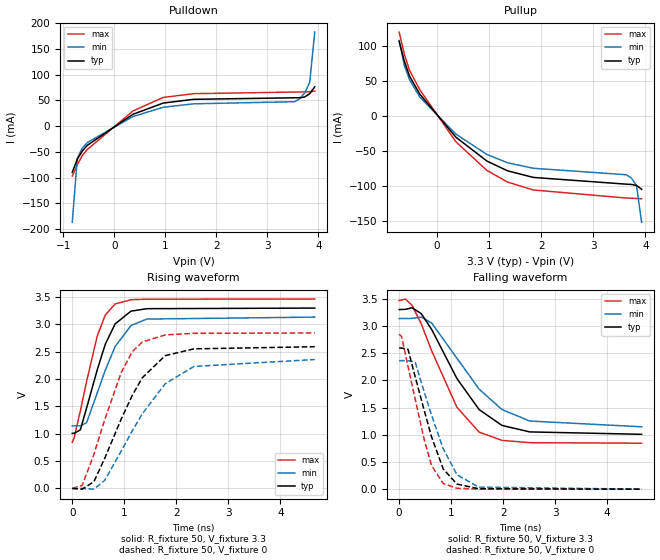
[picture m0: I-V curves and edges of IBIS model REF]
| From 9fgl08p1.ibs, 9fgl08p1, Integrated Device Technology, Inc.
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[Model]   REF
Model_type   Output
Polarity   Non-Inverting
|   typ   min   max
C_comp   2pF   1.5pF   2.5pF
Vmeas = 1.65V
Rref = 50
Cref = 0
Vref = 1.65V
|   typ   min   max
[Voltage range]   3.3V   3.135V   3.465V
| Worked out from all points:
|   slope of the pulldown table from 0 to 0.495 V, typ, clamps not added: 16.9 ohm
|   slope of the pullup table from 0 to 0.495 V, typ, clamps not added: 12.6 ohm
|   rising waveform, R_fixture 50, V_fixture 3.3: 20-80 % time 450ps typ, 507ps min, 388ps max; typ from 1.01 V to 3.3 V
|   falling waveform, R_fixture 50, V_fixture 3.3: 20-80 % time 857ps typ, 970ps min, 739ps max; typ from 3.3 V to 1.01 V
|   rising waveform, R_fixture 50, V_fixture 0: 20-80 % time 771ps typ, 936ps min, 618ps max; typ from 0 V to 2.59 V
|   falling waveform, R_fixture 50, V_fixture 0: 20-80 % time 472ps typ, 527ps min, 413ps max; typ from 2.59 V to 0 V
[Pulldown]
|Voltage   I (typ)   I (min)   I (max)
|Note, modeling breaks down at 250mA and above.  This is well beyond the functional   |
|operating range of the device.  Should this scenario occur, catastrophic failure and   |
|possible damage to the device and/or board is of higher concern than the I-V curve   |
|behavior.  The IBIS checker will flag currents in excess of 10A with warnings.  Lines   |
|with currents in excess of 0.35 A have been commented out.  The points still remain|
|available to the user if the user desires to use them.   |
|-3.30000e+00   -4.58626e+02   -3.98855e+02   -5.58913e+02
|-3.20100e+00   -4.38670e+02   -3.81813e+02   -5.34126e+02
|-3.10200e+00   -4.18718e+02   -3.64776e+02   -5.09343e+02
|-3.00300e+00   -3.98770e+02   -3.47745e+02   -4.84563e+02
|-2.90400e+00   -3.78827e+02   -3.30720e+02   -4.59787e+02
|-2.80500e+00   -3.58890e+02   -3.13701e+02   -4.35015e+02
|-2.70600e+00   -3.38959e+02   -2.96690e+02   -4.10248e+02
|-2.60700e+00   -3.19035e+02   -2.79688e+02   -3.85486e+02
|-2.50800e+00   -2.99119e+02   -2.62696e+02   -3.60731e+02
|-2.40900e+00   -2.79213e+02   -2.45715e+02   -3.35984e+02
|-2.31000e+00   -2.59319e+02   -2.28747e+02   -3.11245e+02
|-2.21100e+00   -2.39437e+02   -2.11796e+02   -2.86516e+02
|-2.11200e+00   -2.19572e+02   -1.94864e+02   -2.61800e+02
|-2.01300e+00   -1.99726e+02   -1.77955e+02   -2.37100e+02
|-1.91400e+00   -1.79905e+02   -1.61075e+02   -2.12419e+02
|-1.81500e+00   -1.60116e+02   -1.44233e+02   -1.87763e+02
|-1.71600e+00   -1.40369e+02   -1.27441e+02   -1.63140e+02
|-1.61700e+00   -1.20682e+02   -1.10717e+02   -1.38565e+02
|-1.51800e+00   -1.01080e+02   -9.40899e+01   -1.14061e+02
|-1.41900e+00   -8.16135e+01   -7.76121e+01   -8.96701e+01
|-1.32000e+00   -6.23864e+01   -6.13830e+01   -6.54941e+01
|-1.22100e+00   -4.36066e+01   -4.55730e+01   -4.17841e+01
|-1.12200e+00   -2.55446e+01   -3.03740e+01   -1.89497e+01
|-1.02300e+00   -8.13369e+00   -1.57511e+01   -1.01906e+00
|-9.24000e-01   -3.55892e-01   -2.38948e+00   -1.27879e-01
-825mV    -89.74mA   -186.9mA   -97.05mA
-726mV    -64.34mA   -62.46mA   -75.03mA
-627mV    -48.3mA    -42.65mA   -56.86mA
-528mV    -37.22mA   -31.89mA   -45.33mA
363mV     22.88mA    18.45mA    29.33mA
957mV     44.74mA    36.62mA    55.73mA
1.551V    52.05mA    43.3mA     63.04mA
3.531V    55.03mA    47.39mA    66.19mA
3.63V     55.21mA    52.95mA    66.32mA
3.729V    56.59mA    64.36mA    66.46mA
3.828V    63.02mA    84.81mA    66.64mA
3.927V    76.26mA    182.8mA    67.99mA
| 4.02600e+00   9.63336e-02   1.95544e+00   7.56685e-02
| 4.12500e+00   1.29319e-01   1.96109e+01   9.19025e-02
| 4.22400e+00   6.62462e-01   4.21550e+01   1.15435e-01
| 4.32300e+00   1.51637e+01   6.47670e+01   1.37492e-01
| 4.42200e+00   4.22442e+01   8.74545e+01   2.35006e-01
| 4.52100e+00   6.94172e+01   1.10195e+02   8.92943e+00
| 4.62000e+00   9.66780e+01   1.32968e+02   4.35589e+01
| 4.71900e+00   1.23991e+02   1.55761e+02   7.83218e+01
| 4.81800e+00   1.51333e+02   1.78569e+02   1.13180e+02
| 4.91700e+00   1.78693e+02   2.01386e+02   1.48085e+02
| 5.01600e+00   2.06065e+02   2.24210e+02   1.83014e+02
| 5.11500e+00   2.33446e+02   2.47041e+02   2.17958e+02
| 5.21400e+00   2.60834e+02   2.69877e+02   2.52912e+02
| 5.31300e+00   2.88228e+02   2.92717e+02   2.87874e+02
| 5.41200e+00   3.15625e+02   3.15560e+02   3.22841e+02
| 5.51100e+00   3.43027e+02   3.38407e+02   3.57813e+02
| 5.61000e+00   3.70432e+02   3.61256e+02   3.92789e+02
| 5.70900e+00   3.97841e+02   3.84108e+02   4.27769e+02
| 5.80800e+00   4.25252e+02   4.06963e+02   4.62752e+02
| 5.90700e+00   4.52666e+02   4.29821e+02   4.97738e+02
| 6.00600e+00   4.80082e+02   4.52680e+02   5.32727e+02
| 6.10500e+00   5.07501e+02   4.75543e+02   5.67718e+02
| 6.20400e+00   5.34922e+02   4.98407e+02   6.02711e+02
| 6.30300e+00   5.62345e+02   5.21273e+02   6.37705e+02
| 6.40200e+00   5.89770e+02   5.44142e+02   6.72701e+02
| 6.50100e+00   6.17197e+02   5.67013e+02   7.07699e+02
| 6.60000e+00   6.44626e+02   5.89886e+02   7.42698e+02
[Pullup]
|Voltage   I (typ)   I (min)   I (max)
|Note, modeling breaks down at 250mA and above.  This is well beyond the functional   |
|operating range of the device.  Should this scenario occur, catastrophic failure and   |
|possible damage to the device and/or board is of higher concern than the I-V curve   |
|behavior.  The IBIS checker will flag currents in excess of 10A with warnings.  Lines   |
|with currents in excess of 0.35 A have been commented out.  The points still remain|
|available to the user if the user desires to use them.   |
|-3.30000e+00   6.44680e+02   5.51825e+02   8.01095e+02
|-3.20100e+00   6.17254e+02   5.28958e+02   7.66095e+02
|-3.10200e+00   5.89830e+02   5.06093e+02   7.31096e+02
|-3.00300e+00   5.62407e+02   4.83230e+02   6.96098e+02
|-2.90400e+00   5.34987e+02   4.60368e+02   6.61102e+02
|-2.80500e+00   5.07568e+02   4.37509e+02   6.26108e+02
|-2.70600e+00   4.80150e+02   4.14651e+02   5.91115e+02
|-2.60700e+00   4.52735e+02   3.91796e+02   5.56124e+02
|-2.50800e+00   4.25322e+02   3.68942e+02   5.21136e+02
|-2.40900e+00   3.97911e+02   3.46091e+02   4.86149e+02
|-2.31000e+00   3.70503e+02   3.23243e+02   4.51165e+02
|-2.21100e+00   3.43097e+02   3.00397e+02   4.16183e+02
|-2.11200e+00   3.15694e+02   2.77554e+02   3.81204e+02
|-2.01300e+00   2.88295e+02   2.54715e+02   3.46229e+02
|-1.91400e+00   2.60900e+02   2.31881e+02   3.11257e+02
|-1.81500e+00   2.33510e+02   2.09052e+02   2.76290e+02
|-1.71600e+00   2.06127e+02   1.86229e+02   2.41329e+02
|-1.61700e+00   1.78751e+02   1.63415e+02   2.06375e+02
|-1.51800e+00   1.51388e+02   1.40613e+02   1.71432e+02
|-1.41900e+00   1.24042e+02   1.17829e+02   1.36506e+02
|-1.32000e+00   9.67252e+01   9.50724e+01   1.01609e+02
|-1.22100e+00   6.94599e+01   7.23604e+01   6.67700e+01
|-1.12200e+00   4.22820e+01   4.97173e+01   3.20469e+01
|-1.02300e+00   1.51962e+01   2.71494e+01   2.11287e+00
|-9.24000e-01   6.89030e-01   5.34223e+00   1.97623e-01
|-8.25000e-01   1.48916e-01   3.54714e-01   1.54087e-01
-726mV    106.9mA    108.2mA    120.1mA
-627mV    78.63mA    72.64mA    88.74mA
-528mV    57.36mA    52.3mA     65.5mA
-330mV    31.45mA    27.24mA    37.82mA
363mV     -30.02mA   -25.58mA   -36.52mA
957mV     -64.05mA   -54.65mA   -77.43mA
1.353V    -77.99mA   -66.51mA   -94.06mA
1.848V    -87.45mA   -74.38mA   -105.4mA
3.63V     -97.08mA   -83.63mA   -116.9mA
3.729V    -97.47mA   -88.18mA   -117.2mA
3.828V    -98.9mA    -99mA      -117.5mA
3.927V    -104.4mA   -151.4mA   -117.9mA
| 4.02600e+00   -1.15410e-01   -9.65481e-01   -1.19366e-01
| 4.12500e+00   -1.36603e-01   -1.09884e+01   -1.26324e-01
| 4.22400e+00   -3.99361e-01   -2.54841e+01   -1.40663e-01
| 4.32300e+00   -8.17474e+00   -4.04654e+01   -1.58277e-01
| 4.42200e+00   -2.55843e+01   -5.60873e+01   -2.17491e-01
| 4.52100e+00   -4.36450e+01   -7.21990e+01   -4.28595e+00
| 4.62000e+00   -6.24226e+01   -8.86071e+01   -2.64922e+01
| 4.71900e+00   -8.16508e+01   -1.05189e+02   -4.96573e+01
| 4.81800e+00   -1.01115e+02   -1.21884e+02   -7.35635e+01
| 4.91700e+00   -1.20715e+02   -1.38656e+02   -9.78285e+01
| 5.01600e+00   -1.40403e+02   -1.55482e+02   -1.22263e+02
| 5.11500e+00   -1.60149e+02   -1.72350e+02   -1.46794e+02
| 5.21400e+00   -1.79938e+02   -1.89250e+02   -1.71387e+02
| 5.31300e+00   -1.99760e+02   -2.06175e+02   -1.96022e+02
| 5.41200e+00   -2.19606e+02   -2.23121e+02   -2.20688e+02
| 5.51100e+00   -2.39472e+02   -2.40084e+02   -2.45378e+02
| 5.61000e+00   -2.59355e+02   -2.57061e+02   -2.70086e+02
| 5.70900e+00   -2.79251e+02   -2.74051e+02   -2.94808e+02
| 5.80800e+00   -2.99159e+02   -2.91052e+02   -3.19543e+02
| 5.90700e+00   -3.19077e+02   -3.08062e+02   -3.44288e+02
| 6.00600e+00   -3.39003e+02   -3.25080e+02   -3.69042e+02
| 6.10500e+00   -3.58937e+02   -3.42106e+02   -3.93803e+02
| 6.20400e+00   -3.78878e+02   -3.59138e+02   -4.18571e+02
| 6.30300e+00   -3.98826e+02   -3.76177e+02   -4.43346e+02
| 6.40200e+00   -4.18779e+02   -3.93221e+02   -4.68125e+02
| 6.50100e+00   -4.38737e+02   -4.10271e+02   -4.92910e+02
| 6.60000e+00   -4.58699e+02   -4.27325e+02   -5.17700e+02
[Ramp]
|   typ   min   max
dV/dt_r   1.566/0.774n   1.425/0.94n   1.718/0.621n
dV/dt_f   1.396/0.866n   1.212/0.979n   1.595/0.746n
R_load =   50
[Rising Waveform]
R_fixture = 50
V_fixture = 3.3   |Vcc_typ
V_fixture_min = 3.135 |Vcc_min
V_fixture_max = 3.465 |Vcc_max
C_fixture = 0.0p
| Time   typ   min   max
0s        1.008V     1.145V     844.6mV
34.71ps   1.008V     1.145V     923.1mV
154.3ps   1.071V     1.145V     1.413V
275.2ps   1.472V     1.202V     1.956V
479.5ps   2.168V     1.745V     2.789V
635.5ps   2.641V     2.166V     3.174V
823.7ps   3.01V      2.596V     3.375V
1.129ns   3.244V     2.981V     3.453V
1.433ns   3.289V     3.099V     3.463V
4.662ns   3.3V       3.135V     3.465V
[Falling Waveform]
R_fixture = 50
V_fixture = 3.3   |Vcc_typ
V_fixture_min = 3.135 |Vcc_min
V_fixture_max = 3.465 |Vcc_max
C_fixture = 0.0p
| Time   typ   min   max
0s        3.3V       3.135V     3.465V
120.3ps   3.304V     3.135V     3.493V
247.8ps   3.333V     3.138V     3.377V
425ps     3.225V     3.162V     3.038V
624.4ps   2.937V     3.054V     2.545V
1.111ns   2.034V     2.407V     1.506V
1.539ns   1.462V     1.838V     1.048V
1.979ns   1.171V     1.463V     896.3mV
2.515ns   1.052V     1.252V     854.4mV
4.666ns   1.008V     1.146V     844.6mV
[Rising Waveform]
R_fixture = 50
V_fixture = 0
C_fixture = 0.0p
| Time   typ   min   max
0s        23.89nV    60.43nV    30.4nV
191.1ps   -13.44mV   129.7uV    54.48mV
415.8ps   124mV      -13.01mV   625.4mV
623.1ps   548.9mV    147.1mV    1.254V
939.4ps   1.267V     680mV      2.117V
1.156ns   1.708V     1.059V     2.505V
1.348ns   2.027V     1.367V     2.681V
1.787ns   2.43V      1.916V     2.809V
2.339ns   2.554V     2.232V     2.838V
4.662ns   2.593V     2.359V     2.845V
[Falling Waveform]
R_fixture = 50
V_fixture = 0
C_fixture = 0.0p
| Time   typ   min   max
0s        2.593V     2.362V     2.845V
47.92ps   2.593V     2.362V     2.804V
169.8ps   2.571V     2.362V     2.258V
309ps     2.063V     2.332V     1.656V
482.9ps   1.445V     1.783V     905.2mV
624.2ps   958.6mV    1.36V      434.3mV
847.8ps   371.4mV    743.3mV    103.8mV
1.113ns   93.12mV    264.4mV    16.96mV
1.53ns    8.102mV    37.41mV    1.012mV
4.662ns   -1.039uV   -794nV     -867.7nV
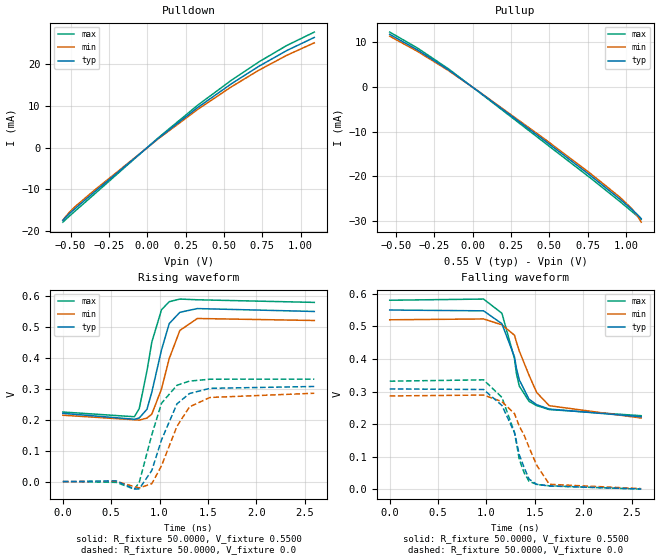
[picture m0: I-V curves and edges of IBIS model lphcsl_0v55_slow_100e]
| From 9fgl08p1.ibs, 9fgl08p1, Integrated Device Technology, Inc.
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[Model]   lphcsl_0v55_slow_100e
Model_type Output
Polarity   Non-Inverting
Enable   Active-High
Vmeas =  0.4000V
Cref =   2.0000pF
Rref =   0.0
Vref =   0.4000V
C_comp   1.1000pF   1.0000pF   1.2000pF
[Temperature Range]   25.0000   85.0000   -40.0000
[Voltage Range]   0.5500V   0.5200V   0.5800V
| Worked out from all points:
|   slope of the pulldown table from 0 to 0.083 V, typ, clamps not added: 32.7 ohm
|   slope of the pullup table from 0 to 0.083 V, typ, clamps not added: 39.3 ohm
|   rising waveform, R_fixture 50.0000, V_fixture 0.5500: 20-80 % time 156ps typ, 172ps min, 137ps max; typ from 0.221 V to 0.551 V
|   rising waveform, R_fixture 50.0000, V_fixture 0.0: 20-80 % time 218ps typ, 257ps min, 187ps max; typ from 0 V to 0.308 V
|   falling waveform, R_fixture 50.0000, V_fixture 0.5500: 20-80 % time 226ps typ, 279ps min, 186ps max; typ from 0.55 V to 0.222 V
|   falling waveform, R_fixture 50.0000, V_fixture 0.0: 20-80 % time 221ps typ, 262ps min, 196ps max; typ from 0.308 V to 0.001 V
[Pulldown]
|Voltage   I(typ)   I(min)   I(max)
-550mV    -17.42mA   -17.37mA   -17.87mA
-510mV    -15.92mA   -15.58mA   -16.5mA
-470mV    -14.59mA   -14.14mA   -15.2mA
-350mV    -10.82mA   -10.4mA    -11.34mA
70mV      2.144mA    2.042mA    2.274mA
330mV     9.616mA    9.161mA    10.17mA
550mV     15.31mA    14.58mA    16.15mA
730mV     19.51mA    18.57mA    20.56mA
910mV     23.24mA    22.1mA     24.45mA
1.09V     26.39mA    25.1mA     27.67mA
[Pullup]
|Voltage   I(typ)   I(min)   I(max)
-540mV    11.78mA    11.36mA    12.28mA
-360mV    8.313mA    7.995mA    8.73mA
-160mV    3.912mA    3.748mA    4.141mA
40mV      -1.02mA    -975.2uA   -1.083mA
480mV     -12.23mA   -11.87mA   -12.71mA
760mV     -19.55mA   -19.1mA    -20.1mA
960mV     -25.05mA   -24.6mA    -25.58mA
1.04V     -27.39mA   -27.24mA   -27.85mA
1.08V     -28.69mA   -29.05mA   -29.01mA
1.1V      -29.42mA   -30.23mA   -29.61mA
[Ramp]
| variable   typ   min   max
dV/dt_r  0.1848/0.2190n   0.1717/0.2485n   0.1991/0.1882n
dV/dt_f  0.1965/0.2484n   0.1808/0.2865n   0.2125/0.2078n
R_load = 50.0000
[Rising Waveform]
R_fixture= 50.0000
V_fixture= 0.5500
V_fixture_min= 0.5200
V_fixture_max= 0.5800
|time   V(typ)   V(min)   V(max)
0s        221mV      214.9mV    225.3mV
740ps     201.9mV    200.2mV    210mV
790ps     206mV      199.1mV    236.4mV
870ps     234.3mV    205.7mV    359.2mV
920ps     290mV      218.6mV    452mV
1.02ns    426.3mV    299.8mV    556.5mV
1.1ns     511.8mV    398.5mV    582.6mV
1.21ns    548.2mV    489.5mV    591.1mV
1.39ns    560.3mV    528.2mV    588.8mV
2.6ns     550.9mV    521.7mV    580.3mV
[Rising Waveform]
R_fixture= 50.0000
V_fixture= 0.0
V_fixture_min= 0.0
V_fixture_max= 0.0
|time   V(typ)   V(min)   V(max)
0s        0V         0V         0V
550ps     2.324mV    951.5uV    -2.512mV
740ps     -24.18mV   -16.37mV   -24.55mV
790ps     -23.47mV   -20.51mV   -2.409mV
920ps     36.17mV    -6.753mV   151.8mV
1.02ns    135mV      51.17mV    253.8mV
1.18ns    251.8mV    179.1mV    311.9mV
1.31ns    285.3mV    242.2mV    325.5mV
1.52ns    302mV      272.4mV    331.5mV
2.6ns     308mV      286.1mV    331.8mV
[Falling Waveform]
R_fixture= 50.0000
V_fixture= 0.5500
V_fixture_min= 0.5200
V_fixture_max= 0.5800
|time   V(typ)   V(min)   V(max)
0s        550mV      520mV      580mV
970ps     547.5mV    522.6mV    583.6mV
1.16ns    508mV      504.6mV    540.1mV
1.29ns    406.3mV    472.7mV    400.4mV
1.31ns    370.9mV    451.9mV    355.2mV
1.34ns    335.5mV    423.9mV    316.5mV
1.44ns    276.5mV    350.4mV    269.9mV
1.52ns    259.5mV    296.8mV    256.6mV
1.65ns    246.1mV    256.4mV    244.6mV
2.6ns     222.5mV    218.6mV    225.8mV
[Falling Waveform]
R_fixture= 50.0000
V_fixture= 0.0
V_fixture_min= 0.0
V_fixture_max= 0.0
|time   V(typ)   V(min)   V(max)
0s        307.9mV    286.4mV    331.7mV
970ps     306.1mV    289.1mV    335.8mV
1.16ns    257.3mV    269.1mV    282mV
1.29ns    173.9mV    232mV      174.5mV
1.34ns    105.8mV    193.4mV    91.43mV
1.39ns    66.68mV    165.9mV    50.82mV
1.44ns    31.41mV    129mV      24.81mV
1.52ns    15.24mV    73.8mV     14.68mV
1.65ns    10.13mV    15.34mV    10.72mV
2.6ns     993.4uV    2.118mV    402uV
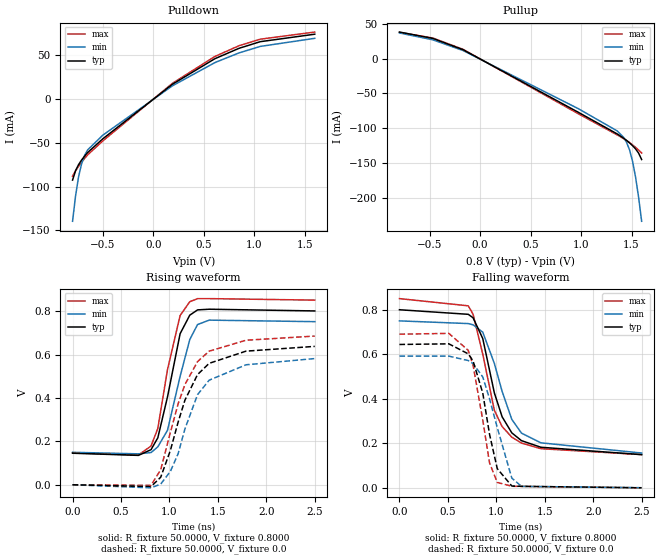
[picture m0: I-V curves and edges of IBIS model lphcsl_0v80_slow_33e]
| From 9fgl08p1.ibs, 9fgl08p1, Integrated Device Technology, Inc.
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[Model]   lphcsl_0v80_slow_33e
Model_type Output
Polarity   Inverting
Enable   Active-High
Vmeas =  0.4000V
Cref =   2.0000pF
Rref =   0.0
Vref =   0.4000V
C_comp   1.1000pF   1.0000pF   1.2000pF
[Temperature Range]   25.0000   85.0000   -40.0
[Voltage Range]   0.8000V   0.7500V   0.8500V
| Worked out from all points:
|   slope of the pulldown table from 0 to 0.12 V, typ, clamps not added: 11 ohm
|   slope of the pullup table from 0 to 0.12 V, typ, clamps not added: 12.1 ohm
|   rising waveform, R_fixture 50.0000, V_fixture 0.8000: 20-80 % time 177ps typ, 192ps min, 166ps max; typ from 0.145 V to 0.801 V
|   rising waveform, R_fixture 50.0000, V_fixture 0.0: 20-80 % time 305ps typ, 313ps min, 304ps max; typ from 0 V to 0.638 V
|   falling waveform, R_fixture 50.0000, V_fixture 0.8000: 20-80 % time 245ps typ, 283ps min, 242ps max; typ from 0.8 V to 0.149 V
|   falling waveform, R_fixture 50.0000, V_fixture 0.0: 20-80 % time 180ps typ, 212ps min, 162ps max; typ from 0.644 V to 0.001 V
[Pulldown]
|Voltage   I(typ)   I(min)   I(max)
-800mV    -92.57mA   -139.6mA   -88.06mA
-770mV    -81.83mA   -110.4mA   -81.92mA
-740mV    -74.86mA   -88.54mA   -76.8mA
-710mV    -69.59mA   -73.71mA   -72.12mA
-680mV    -65.11mA   -64.26mA   -67.77mA
-650mV    -61.1mA    -58.06mA   -63.76mA
-500mV    -45.44mA   -41.28mA   -47.88mA
190mV     16.84mA    15.05mA    17.9mA
610mV     45.97mA    41.51mA    48.54mA
850mV     57.86mA    52.62mA    60.82mA
1.06V     65.41mA    60.01mA    68.26mA
1.6V      73.95mA    69.24mA    76.41mA
[Pullup]
|Voltage   I(typ)   I(min)   I(max)
-800mV    38.28mA    36.96mA    37.81mA
-470mV    29.15mA    27.13mA    29.71mA
-170mV    12.86mA    11.67mA    13.38mA
970mV     -77.08mA   -71.89mA   -79.17mA
1.36V     -108.6mA   -104.3mA   -110mA
1.42V     -114.4mA   -113.2mA   -115.1mA
1.45V     -117.7mA   -120.3mA   -117.9mA
1.48V     -121.3mA   -131.3mA   -120.9mA
1.51V     -125.3mA   -147.8mA   -124.2mA
1.54V     -130mA     -170.7mA   -127.8mA
1.57V     -136.1mA   -199.7mA   -131.7mA
1.6V      -145.3mA   -234.2mA   -135.9mA
[Ramp]
| variable   typ   min   max
dV/dt_r  0.3825/0.3223n   0.3488/0.3361n   0.4110/0.3169n
dV/dt_f  0.3904/0.2433n   0.3560/0.2784n   0.4202/0.2382n
R_load = 50.0000
[Rising Waveform]
R_fixture= 50.0000
V_fixture= 0.8000
V_fixture_min= 0.7500
V_fixture_max= 0.8500
|time   V(typ)   V(min)   V(max)
0s        145.3mV    149.5mV    146.9mV
680ps     135.3mV    142.4mV    137.3mV
810ps     161.7mV    148.4mV    178.3mV
880ps     216.2mV    174.7mV    259.4mV
980ps     405mV      251mV      530.6mV
1.11ns    695.8mV    499.1mV    779.5mV
1.21ns    781.3mV    669.1mV    843.3mV
1.29ns    805.6mV    738mV      857.5mV
1.41ns    808.7mV    758.4mV    857.6mV
2.5ns     800.8mV    751.4mV    850.6mV
[Rising Waveform]
R_fixture= 50.0000
V_fixture= 0.0
V_fixture_min= 0.0
V_fixture_max= 0.0
|time   V(typ)   V(min)   V(max)
0s        0V         0V         0V
810ps     -8.36mV    -14.19mV   -2.481mV
910ps     34.82mV    3.011mV    69.66mV
1.01ns    158.6mV    61.78mV    241.8mV
1.09ns    289.1mV    143.5mV    373.5mV
1.16ns    389.9mV    257.5mV    462mV
1.29ns    507.6mV    415.3mV    567.3mV
1.41ns    559.4mV    481.7mV    615.5mV
1.79ns    615.5mV    552.6mV    665.8mV
2.5ns     637.5mV    581.4mV    685mV
[Falling Waveform]
R_fixture= 50.0000
V_fixture= 0.8000
V_fixture_min= 0.7500
V_fixture_max= 0.8500
|time   V(typ)   V(min)   V(max)
0s        800mV      750mV      850mV
710ps     779.5mV    737.9mV    817.6mV
760ps     764mV      732.4mV    780mV
860ps     670.8mV    699.3mV    600.7mV
980ps     426.3mV    558.7mV    348.4mV
1.06ns    319.3mV    433.3mV    275.5mV
1.16ns    247.1mV    307.5mV    227.8mV
1.26ns    212.2mV    245.9mV    201.4mV
1.46ns    182.6mV    202.5mV    176.1mV
2.5ns     149.4mV    156.7mV    149.7mV
[Falling Waveform]
R_fixture= 50.0000
V_fixture= 0.0
V_fixture_min= 0.0
V_fixture_max= 0.0
|time   V(typ)   V(min)   V(max)
0s        644.1mV    591.7mV    690.2mV
510ps     646.9mV    591.8mV    693.9mV
710ps     602mV      571.9mV    617.6mV
760ps     570.1mV    558mV      551.2mV
860ps     426.3mV    498.5mV    305.4mV
930ps     240.8mV    400.4mV    112.6mV
1.01ns    86.46mV    270.3mV    24.7mV
1.16ns    8.565mV    43.99mV    7.458mV
1.26ns    7.158mV    7.085mV    6.902mV
2.5ns     589.6uV    1.009mV    417.2uV
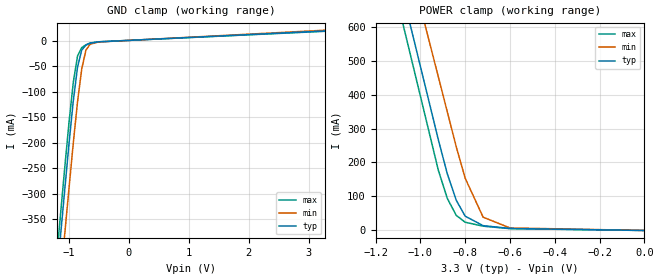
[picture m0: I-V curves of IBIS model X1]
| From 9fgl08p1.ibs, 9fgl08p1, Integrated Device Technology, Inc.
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|   Model X1
[Model]  X1
Model_type Input
Polarity   Non-Inverting
Enable   Active-High
Vinl =   0.8000V
Vinh =   2.0000V
C_comp   1.1000pF   1.0000pF   1.2000pF
[Temperature Range]   25.0000   85.0000   -40.0
[Voltage Range]   3.3000V   3.0000V   3.6000V
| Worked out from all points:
|   GND clamp passes 1 mA (typ) near -0.23 V on its own axis
|   POWER clamp passes 1 mA (typ) near -0.23 V on its own axis
[GND_clamp]
|Voltage   I(typ)   I(min)   I(max)
-3.3V     -3.176A    -3.199A    -3.165A
-1.2V     -469mA     -551.8mA   -427.9mA
-1.13V    -378.8mA   -463.6mA   -336.7mA
-1.06V    -288.6mA   -375.3mA   -245.5mA
-990mV    -199.5mA   -287.1mA   -158.1mA
-920mV    -117.7mA   -200mA     -81.31mA
-850mV    -51.99mA   -120.2mA   -30.07mA
-780mV    -18.37mA   -55.55mA   -13.71mA
-710mV    -8.888mA   -18.57mA   -8.034mA
-640mV    -4.93mA    -6.911mA   -4.472mA
-500mV    -2.286mA   -2.553mA   -2.176mA
3.28V     19.14mA    20.57mA    18.42mA
[POWER_clamp]
|Voltage   I(typ)   I(min)   I(max)
-3.28V    6.627A     6.524A     6.687A
-1.2V     1.021A     1.172A     944.6mA
-1.16V    914.1mA    1.069A     834.2mA
-1.12V    806.3mA    966.9mA    723.8mA
-1.08V    698.5mA    864mA      613.4mA
-920mV    267.4mA    452.4mA    177.5mA
-880mV    167.1mA    349.4mA    94.63mA
-840mV    89.12mA    246.6mA    44.57mA
-800mV    42.04mA    153.7mA    24.23mA
-720mV    14.18mA    39.19mA    12.66mA
-600mV    5.902mA    7.459mA    5.394mA
0V        83.65pA    148.3pA    106.8pA
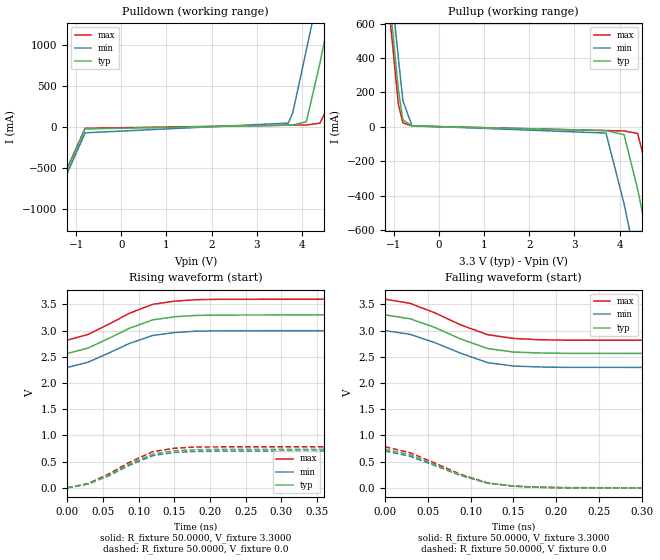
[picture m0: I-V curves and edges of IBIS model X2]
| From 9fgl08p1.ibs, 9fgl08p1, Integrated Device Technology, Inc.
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|   Model X2
[Model]  X2
Model_type Output
Polarity   Non-Inverting
Enable   Active-High
Vmeas =  1.5000V
Cref =   5.0000pF
Rref =   0.0
Vref =   1.5000V
C_comp   1.1000pF   1.0000pF   1.2000pF
[Temperature Range]   25.0000   85.0000   -40.0
[Voltage Range]   3.3000V   3.0000V   3.6000V
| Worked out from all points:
|   slope of the pulldown table from 0 to 0.495 V, typ, clamps not added: 224 ohm
|   slope of the pullup table from 0 to 0.495 V, typ, clamps not added: 224 ohm
|   rising waveform, R_fixture 50.0000, V_fixture 3.3000: 20-80 % time 73.2ps typ, 73.7ps min, 72.7ps max; typ from 2.56 V to 3.3 V
|   rising waveform, R_fixture 50.0000, V_fixture 0.0: 20-80 % time 69ps typ, 68.8ps min, 68.5ps max; typ from 0 V to 0.737 V
|   falling waveform, R_fixture 50.0000, V_fixture 3.3000: 20-80 % time 68.8ps typ, 69.4ps min, 69.7ps max; typ from 3.3 V to 2.56 V
|   falling waveform, R_fixture 50.0000, V_fixture 0.0: 20-80 % time 72.5ps typ, 73ps min, 72.1ps max; typ from 0.737 V to 0 V
[Pulldown]
|Voltage   I(typ)   I(min)   I(max)
-3.3V     -3.176A    -3.199A    -3.165A
-2.3V     -1.887A    -1.938A    -1.862A
-800mV    -24.34mA   -71.77mA   -16.25mA
3.7V      21.78mA    46.81mA    20.92mA
3.8V      23.01mA    173.7mA    21.52mA
4.1V      62.55mA    935.6mA    23.76mA
4.4V      773.1mA    1.707A     45.75mA
4.5V      1.042A     1.964A     154.2mA
4.8V      1.85A      2.736A     966.3mA
5.1V      2.659A     3.507A     1.794A
5.2V      2.928A     3.765A     2.07A
6.6V      6.702A     7.367A     5.935A
[Pullup]
|Voltage   I(typ)   I(min)   I(max)
-3.3V     6.681A     6.575A     6.742A
-1.2V     1.021A     1.172A     944.6mA
-1.1V     752.4mA    915.5mA    668.6mA
-900mV    215.1mA    400.9mA    132.6mA
-800mV    42.04mA    153.7mA    24.23mA
-600mV    5.902mA    7.459mA    5.394mA
3.7V      -21.74mA   -35.7mA    -20.92mA
4.1V      -44.86mA   -445.9mA   -23.34mA
4.4V      -360.7mA   -824.1mA   -37.79mA
4.8V      -876.4mA   -1.328A    -449.6mA
5.2V      -1.392A    -1.832A    -971mA
6.6V      -3.197A    -3.598A    -2.796A
[Ramp]
| variable   typ   min   max
dV/dt_r  0.4422/66.3411p   0.4225/66.1306p   0.4703/65.9042p
dV/dt_f  0.4428/66.0942p   0.4224/66.6346p   0.4704/66.9646p
R_load = 50.0000
[Rising Waveform]
R_fixture= 50.0000
V_fixture= 3.3000
V_fixture_min= 3.0000
V_fixture_max= 3.6000
|time   V(typ)   V(min)   V(max)
0s        2.562V     2.295V     2.816V
29.29ps   2.667V     2.396V     2.926V
58.59ps   2.852V     2.573V     3.124V
87.88ps   3.048V     2.758V     3.334V
120ps     3.205V     2.907V     3.501V
150ps     3.263V     2.962V     3.561V
180ps     3.289V     2.989V     3.589V
210ps     3.296V     2.995V     3.596V
290ps     3.298V     2.998V     3.598V
2.9ns     3.3V       3V         3.6V
[Rising Waveform]
R_fixture= 50.0000
V_fixture= 0.0
V_fixture_min= 0.0
V_fixture_max= 0.0
|time   V(typ)   V(min)   V(max)
0s        0V         0V         0V
29.29ps   75.21mV    71.29mV    81.19mV
58.59ps   244.5mV    231.1mV    266.6mV
87.88ps   459mV      434.5mV    492.1mV
120ps     641.9mV    614.5mV    690.5mV
150ps     708.7mV    675.8mV    755.4mV
180ps     727.5mV    693.8mV    780mV
210ps     733.4mV    701.7mV    781.6mV
290ps     735.5mV    702.6mV    782.2mV
2.9ns     737mV      704.1mV    783.8mV
[Falling Waveform]
R_fixture= 50.0000
V_fixture= 3.3000
V_fixture_min= 3.0000
V_fixture_max= 3.6000
|time   V(typ)   V(min)   V(max)
0s        3.3V       3V         3.6V
29.29ps   3.226V     2.93V      3.52V
58.59ps   3.058V     2.768V     3.337V
87.88ps   2.843V     2.572V     3.112V
120ps     2.657V     2.388V     2.921V
150ps     2.591V     2.324V     2.851V
180ps     2.573V     2.306V     2.825V
210ps     2.566V     2.298V     2.818V
410ps     2.563V     2.297V     2.817V
2.9ns     2.562V     2.296V     2.816V
[Falling Waveform]
R_fixture= 50.0000
V_fixture= 0.0
V_fixture_min= 0.0
V_fixture_max= 0.0
|time   V(typ)   V(min)   V(max)
0s        737.4mV    704mV      783.8mV
29.29ps   631mV      602.4mV    671.7mV
58.59ps   443.6mV    423.2mV    471.1mV
87.88ps   246.7mV    237.1mV    260.8mV
120ps     90.07mV    88.34mV    93.95mV
150ps     32.71mV    33.22mV    33.74mV
180ps     11.05mV    10.98mV    11mV
210ps     2.96mV     3.265mV    2.896mV
290ps     1.717mV    1.764mV    1.739mV
2.9ns     26.75uV    18.94uV    32.76uV
